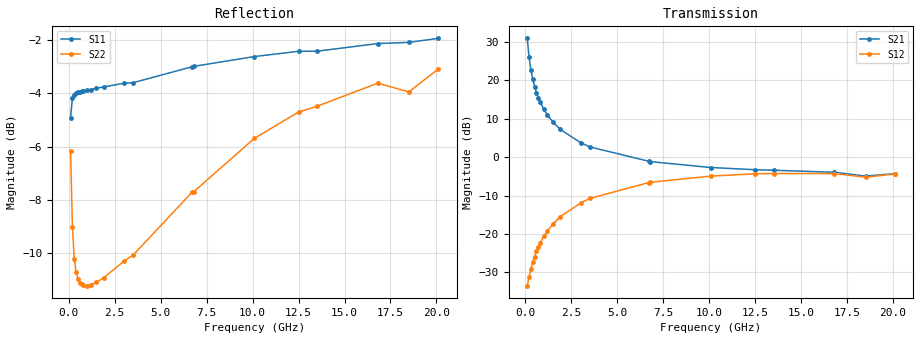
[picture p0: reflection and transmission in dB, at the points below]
!  Infineon Technologies AG
! BFR380L3 , PF131585-7, No.6, Th 09.10.01, soldered on pcb-board, measured with PP GSG850
!  Vce=0.75 V,  Ic=50.0 mA
! Common Emitter S-Parameters:  15. November 2001
#  GHz  S  MA  R  50
! f  S11  S21  S12  S22
! GHz  Mag  Ang  Mag  Ang  Mag  Ang  Mag  Ang
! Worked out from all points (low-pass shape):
!   201 points, 100 MHz to 20.1 GHz, reference 50 ohm
!   highest |S21| = 30.90 dB at 100 MHz (marker M1); lowest = -4.9 dB at 18.5 GHz (marker M2)
!   |S21| within 3 dB of the highest: start of sweep to 160.3 MHz
!   lowest |S11| = -4.9 dB at 100 MHz (marker M3), VSWR 3.63, Z = 16.6 - j21.5 ohm
!   |S11| at or under -10 dB: nowhere
!   |S22| runs from -11.2 to -3.1 dB; largest |S21 - S12| = 35
!   S11 on the Smith chart (normalised r, x): 100 MHz: 0.33, -0.43; 500 MHz: 0.22, -0.03; 3 GHz: 0.23, +0.35; 6.7 GHz: 0.29, +0.82; 12.5 GHz: 0.49, +1.54; 20.1 GHz: 0.97, +2.62
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0.1  0.5677 -129.4  35.06 120.6  0.02129 52.4  0.4916 -85.5
0.2  0.618 -154.9  19.77 104.1  0.02764 53.9  0.3542 -119.1
0.3  0.625 -165.6  13.56 97.2  0.03521 59.1  0.309 -136.4
0.4  0.6325 -171.7  10.29 92.8  0.04287 62.6  0.2916 -146.9
0.5  0.6344 -175.8  8.276 89.4  0.051 65.1  0.2833 -154.0
0.6  0.6343 -179.2  6.919 86.7  0.0593 66.7  0.2786 -159.0
0.7  0.6358 178.0  5.954 84.3  0.0677 67.6  0.2768 -162.9
0.8  0.637 175.5  5.226 82.1  0.07623 68.3  0.2755 -166.0
1  0.6384 171.2  4.21 78.2  0.09315 68.5  0.2748 -170.8
1.2  0.6405 167.3  3.529 74.5  0.1101 68.2  0.2762 -174.4
1.5  0.6448 162.0  2.854 69.5  0.1351 67.0  0.2788 -178.8
1.9  0.6481 155.6  2.294 63.2  0.1681 64.5  0.2844 176.5
3  0.6587 139.7  1.542 47.7  0.2535 56.5  0.3053 165.8
3.5  0.6602 133.1  1.36 41.5  0.2903 52.4  0.3136 161.6
6.7  0.7071 98.6  0.8846 11.4  0.4663 27.7  0.4112 134.0
6.8  0.7085 97.7  0.8743 10.6  0.4713 26.8  0.4124 133.1
10.1  0.7391 74.3  0.7325 -8.2  0.5672 5.4  0.5193 109.5
12.5  0.7561 62.2  0.6862 -19.3  0.6065 -8.4  0.5817 93.1
13.5  0.7564 57.8  0.6756 -23.2  0.6124 -13.9  0.5962 87.4
16.8  0.7817 46.4  0.6358 -34.6  0.6103 -28.4  0.6589 70.0
18.5  0.7858 44.5  0.5667 -41.9  0.549 -36.4  0.6346 65.8
20.1  0.7995 37.6  0.6109 -45.3  0.6029 -41.0  0.7004 56.0
